VERSION 5.8 ;
BUSBITCHARS "<>" ;
DIVIDERCHAR "/" ;

UNITS
   DATABASE MICRONS 2000 ;
   CAPACITANCE PICOFARADS 10 ;
END UNITS

MANUFACTURINGGRID 0.005 ;

LAYER M2
   TYPE ROUTING ;
   WIDTH 1 ;
   PITCH 2 ;
   DIRECTION VERTICAL ;
END M2

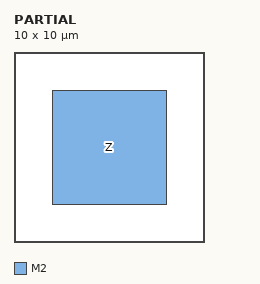
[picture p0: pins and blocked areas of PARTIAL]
MACRO PARTIAL
   CLASS CORE ;
   SIZE 10 BY 10 ;
   PIN Z
      DIRECTION OUTPUT ;
      PORT
         LAYER M2 ;
         RECT 2 2 8 8 ;
      END
   END Z
END PARTIAL

this is not valid LEF syntax @#$%
